VERSION 5.8 ;
BUSBITCHARS "[]" ;
DIVIDERCHAR "/" ;

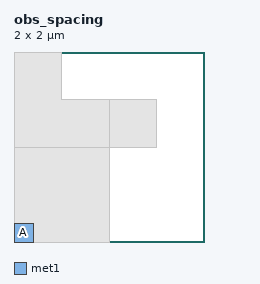
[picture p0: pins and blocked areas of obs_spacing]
MACRO obs_spacing
  CLASS CORE ;
  ORIGIN 0 0 ;
  SIZE 2 BY 2 ;
  PIN A
    DIRECTION INPUT ;
    PORT
      LAYER met1 SPACING 0.1 ;
        RECT 0 0 0.2 0.2 ;
    END
  END A
  OBS
    LAYER met1 SPACING 0.2 ;
      RECT 0.5 0.5 1 1 ;
    LAYER met1 ;
      RECT 1 1 1.5 1.5 ;
    LAYER met2 DESIGNRULEWIDTH 0.3 ;
      RECT 0 0 1 1 ;
    LAYER met3 SPACING 0 ;
      RECT 0 0 1 1 ;
    LAYER met1 SPACING 0.2 ;
      POLYGON 0 1 1 1 1 1.5 0.5 1.5 0.5 2 0 2 ;
  END
END obs_spacing

END LIBRARY
